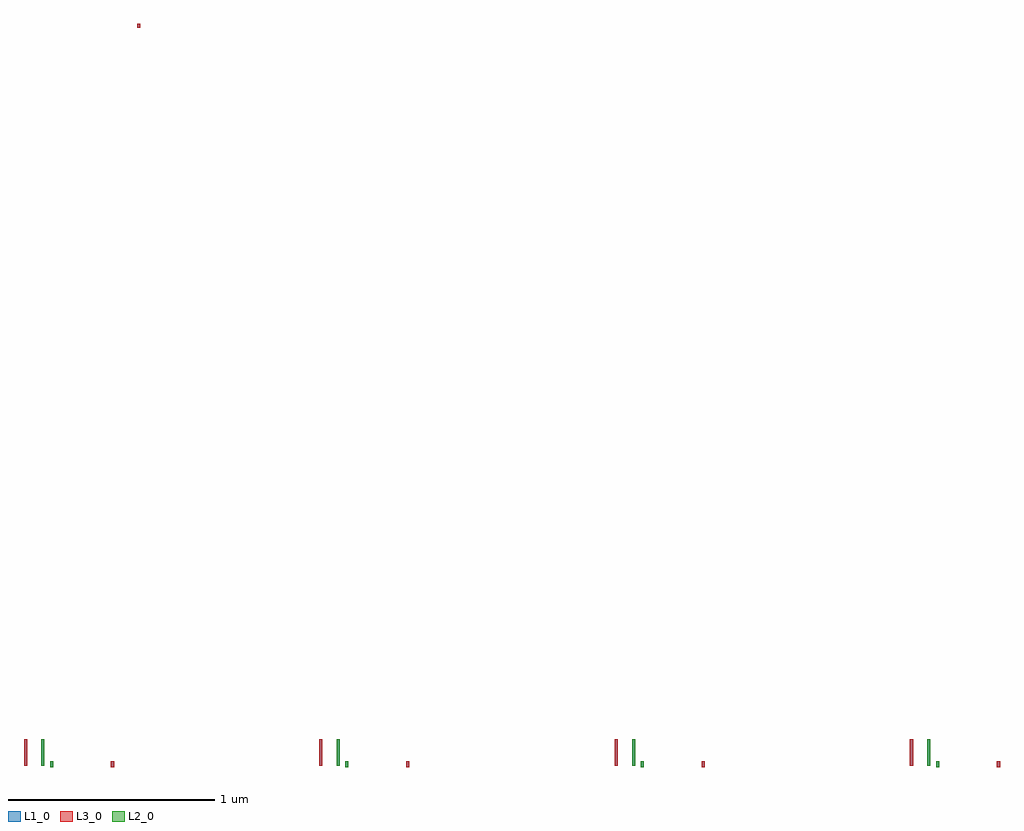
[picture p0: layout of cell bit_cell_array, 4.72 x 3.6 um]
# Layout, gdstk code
import gdstk
lib = gdstk.Library(unit=1e-6, precision=5e-10)
def R(c, l, rs):  # rectangles x0, y0, x1, y1
    for r in rs: c.add(gdstk.rectangle(r[:2], r[2:], *l))
L1_0 = (1, 0)
L2_0 = (2, 0)
L3_0 = (3, 0)

write_driver = lib.new_cell('Write_Driver')
R(write_driver, L1_0, [(0.0645,0.1195,0.0795,0.1495), (0.359,0.1195,0.374,0.1495), (-0.0615,0.1275,-0.0465,0.2555), (0.0225,0.128,0.0375,0.2545)])
R(write_driver, L2_0, [(0.0645,0.1195,0.0795,0.1495), (0.0225,0.128,0.0375,0.2545)])
R(write_driver, L3_0, [(0.359,0.1195,0.374,0.1495), (-0.0615,0.1275,-0.0465,0.2555)])

bit_cell_array = lib.new_cell('bit_cell_array')
R(bit_cell_array, L1_0, [(0.172,-7.467,0.187,-7.447), (1.6005,-7.467,1.6155,-7.447), (3.0295,-7.467,3.0445,-7.447), (4.458,-7.467,4.473,-7.447), (0.088,-7.466,0.103,-7.446), (1.5165,-7.466,1.5315,-7.446), (2.9455,-7.466,2.9605,-7.446), (4.374,-7.466,4.389,-7.446), (0.6365,-4.0045,0.6515,-3.9845)])
R(bit_cell_array, L3_0, [(0.6365,-4.0045,0.6515,-3.9845)])
bit_cell_array.add(gdstk.Reference(write_driver, (0.1495,-7.7015)))
bit_cell_array.add(gdstk.Reference(write_driver, (1.578,-7.7015)))
bit_cell_array.add(gdstk.Reference(write_driver, (4.4355,-7.7015)))
bit_cell_array.add(gdstk.Reference(write_driver, (3.007,-7.7015)))

lib.write_gds('bit_cell_array.gds')
